VERSION 5.7 ;
  NOWIREEXTENSIONATPIN ON ;
  DIVIDERCHAR "/" ;
  BUSBITCHARS "[]" ;
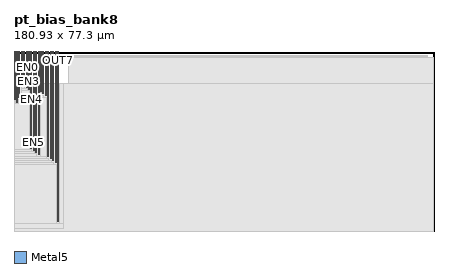
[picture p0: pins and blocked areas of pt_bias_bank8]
MACRO pt_bias_bank8
  CLASS BLOCK ;
  FOREIGN pt_bias_bank8 ;
  ORIGIN -0.300 76.080 ;
  SIZE 180.930 BY 77.300 ;
  PIN VDD
    DIRECTION INOUT ;
    USE POWER ;
    PORT
      LAYER Metal5 ;
        RECT 0.300 -19.620 0.740 1.220 ;
    END
  END VDD
  PIN VSS
    DIRECTION INOUT ;
    USE GROUND ;
    PORT
      LAYER Metal5 ;
        RECT 1.340 -20.520 1.780 1.220 ;
    END
  END VSS
  PIN TRK
    DIRECTION INPUT ;
    USE SIGNAL ;
    ANTENNAGATEAREA 360.000000 ;
    ANTENNADIFFAREA 2.600000 ;
    PORT
      LAYER Metal5 ;
        RECT 2.380 -18.720 2.820 1.220 ;
    END
  END TRK
  PIN EN0
    DIRECTION INPUT ;
    USE SIGNAL ;
    ANTENNAGATEAREA 3.360000 ;
    PORT
      LAYER Metal5 ;
        RECT 3.420 -12.420 3.860 1.220 ;
    END
  END EN0
  PIN EN1
    DIRECTION INPUT ;
    USE SIGNAL ;
    ANTENNAGATEAREA 3.360000 ;
    PORT
      LAYER Metal5 ;
        RECT 4.460 -13.320 4.900 1.220 ;
    END
  END EN1
  PIN EN2
    DIRECTION INPUT ;
    USE SIGNAL ;
    ANTENNAGATEAREA 3.360000 ;
    PORT
      LAYER Metal5 ;
        RECT 5.500 -14.220 5.940 1.220 ;
    END
  END EN2
  PIN EN3
    DIRECTION INPUT ;
    USE SIGNAL ;
    ANTENNAGATEAREA 3.360000 ;
    PORT
      LAYER Metal5 ;
        RECT 6.540 -15.120 6.980 1.220 ;
    END
  END EN3
  PIN EN4
    DIRECTION INPUT ;
    USE SIGNAL ;
    ANTENNAGATEAREA 3.360000 ;
    PORT
      LAYER Metal5 ;
        RECT 7.580 -40.480 8.020 1.220 ;
    END
  END EN4
  PIN EN5
    DIRECTION INPUT ;
    USE SIGNAL ;
    ANTENNAGATEAREA 3.360000 ;
    PORT
      LAYER Metal5 ;
        RECT 8.620 -41.380 9.060 1.220 ;
    END
  END EN5
  PIN EN6
    DIRECTION INPUT ;
    USE SIGNAL ;
    ANTENNAGATEAREA 3.360000 ;
    PORT
      LAYER Metal5 ;
        RECT 9.660 -42.280 10.100 1.220 ;
    END
  END EN6
  PIN EN7
    DIRECTION INPUT ;
    USE SIGNAL ;
    ANTENNAGATEAREA 3.360000 ;
    PORT
      LAYER Metal5 ;
        RECT 10.700 -43.180 11.140 1.220 ;
    END
  END EN7
  PIN OUT0
    DIRECTION OUTPUT ;
    USE SIGNAL ;
    ANTENNADIFFAREA 3.520000 ;
    PORT
      LAYER Metal5 ;
        RECT 11.740 -16.020 12.180 1.220 ;
    END
  END OUT0
  PIN OUT1
    DIRECTION OUTPUT ;
    USE SIGNAL ;
    ANTENNADIFFAREA 3.520000 ;
    PORT
      LAYER Metal5 ;
        RECT 12.780 -16.920 13.220 1.220 ;
    END
  END OUT1
  PIN OUT2
    DIRECTION OUTPUT ;
    USE SIGNAL ;
    ANTENNADIFFAREA 3.520000 ;
    PORT
      LAYER Metal5 ;
        RECT 13.820 -17.820 14.260 1.220 ;
    END
  END OUT2
  PIN OUT3
    DIRECTION OUTPUT ;
    USE SIGNAL ;
    ANTENNADIFFAREA 3.520000 ;
    PORT
      LAYER Metal5 ;
        RECT 14.860 -44.080 15.300 1.220 ;
    END
  END OUT3
  PIN OUT4
    DIRECTION OUTPUT ;
    USE SIGNAL ;
    ANTENNADIFFAREA 3.520000 ;
    PORT
      LAYER Metal5 ;
        RECT 15.900 -44.980 16.340 1.220 ;
    END
  END OUT4
  PIN OUT5
    DIRECTION OUTPUT ;
    USE SIGNAL ;
    ANTENNADIFFAREA 3.520000 ;
    PORT
      LAYER Metal5 ;
        RECT 16.940 -45.880 17.380 1.220 ;
    END
  END OUT5
  PIN OUT6
    DIRECTION OUTPUT ;
    USE SIGNAL ;
    ANTENNADIFFAREA 3.520000 ;
    PORT
      LAYER Metal5 ;
        RECT 17.980 -46.780 18.420 1.220 ;
    END
  END OUT6
  PIN OUT7
    DIRECTION OUTPUT ;
    USE SIGNAL ;
    ANTENNADIFFAREA 3.520000 ;
    PORT
      LAYER Metal5 ;
        RECT 19.020 -72.140 19.460 1.220 ;
    END
  END OUT7
  OBS
      LAYER Nwell ;
        RECT 24.690 -69.980 178.630 -0.600 ;
      LAYER Metal1 ;
        RECT 24.875 -69.880 178.530 -0.785 ;
      LAYER Metal2 ;
        RECT 23.790 -69.880 181.230 -1.360 ;
      LAYER Metal3 ;
        RECT 23.790 -76.080 181.230 -1.360 ;
      LAYER Metal4 ;
        RECT 0.320 -76.080 181.230 -12.360 ;
      LAYER Metal5 ;
        RECT 3.420 -13.920 3.860 -13.020 ;
        RECT 3.420 -14.820 4.900 -13.920 ;
        RECT 3.420 -15.720 5.940 -14.820 ;
        RECT 3.420 -19.320 6.980 -15.720 ;
        RECT 0.300 -19.900 0.380 -19.620 ;
        RECT 0.300 -21.120 0.740 -19.900 ;
        RECT 2.380 -21.120 6.980 -19.320 ;
        RECT 0.300 -41.080 6.980 -21.120 ;
        RECT 11.740 -17.520 12.180 -16.620 ;
        RECT 11.740 -18.420 13.220 -17.520 ;
        RECT 0.300 -41.980 8.020 -41.080 ;
        RECT 0.300 -42.880 9.060 -41.980 ;
        RECT 0.300 -43.780 10.100 -42.880 ;
        RECT 11.740 -43.780 14.260 -18.420 ;
        RECT 0.300 -44.680 14.260 -43.780 ;
        RECT 0.300 -45.580 15.300 -44.680 ;
        RECT 0.300 -46.480 16.340 -45.580 ;
        RECT 0.300 -47.380 17.380 -46.480 ;
        RECT 0.300 -72.740 18.420 -47.380 ;
        RECT 20.060 -72.740 21.540 -12.420 ;
        RECT 0.300 -75.200 21.540 -72.740 ;
  END
END pt_bias_bank8
END LIBRARY

